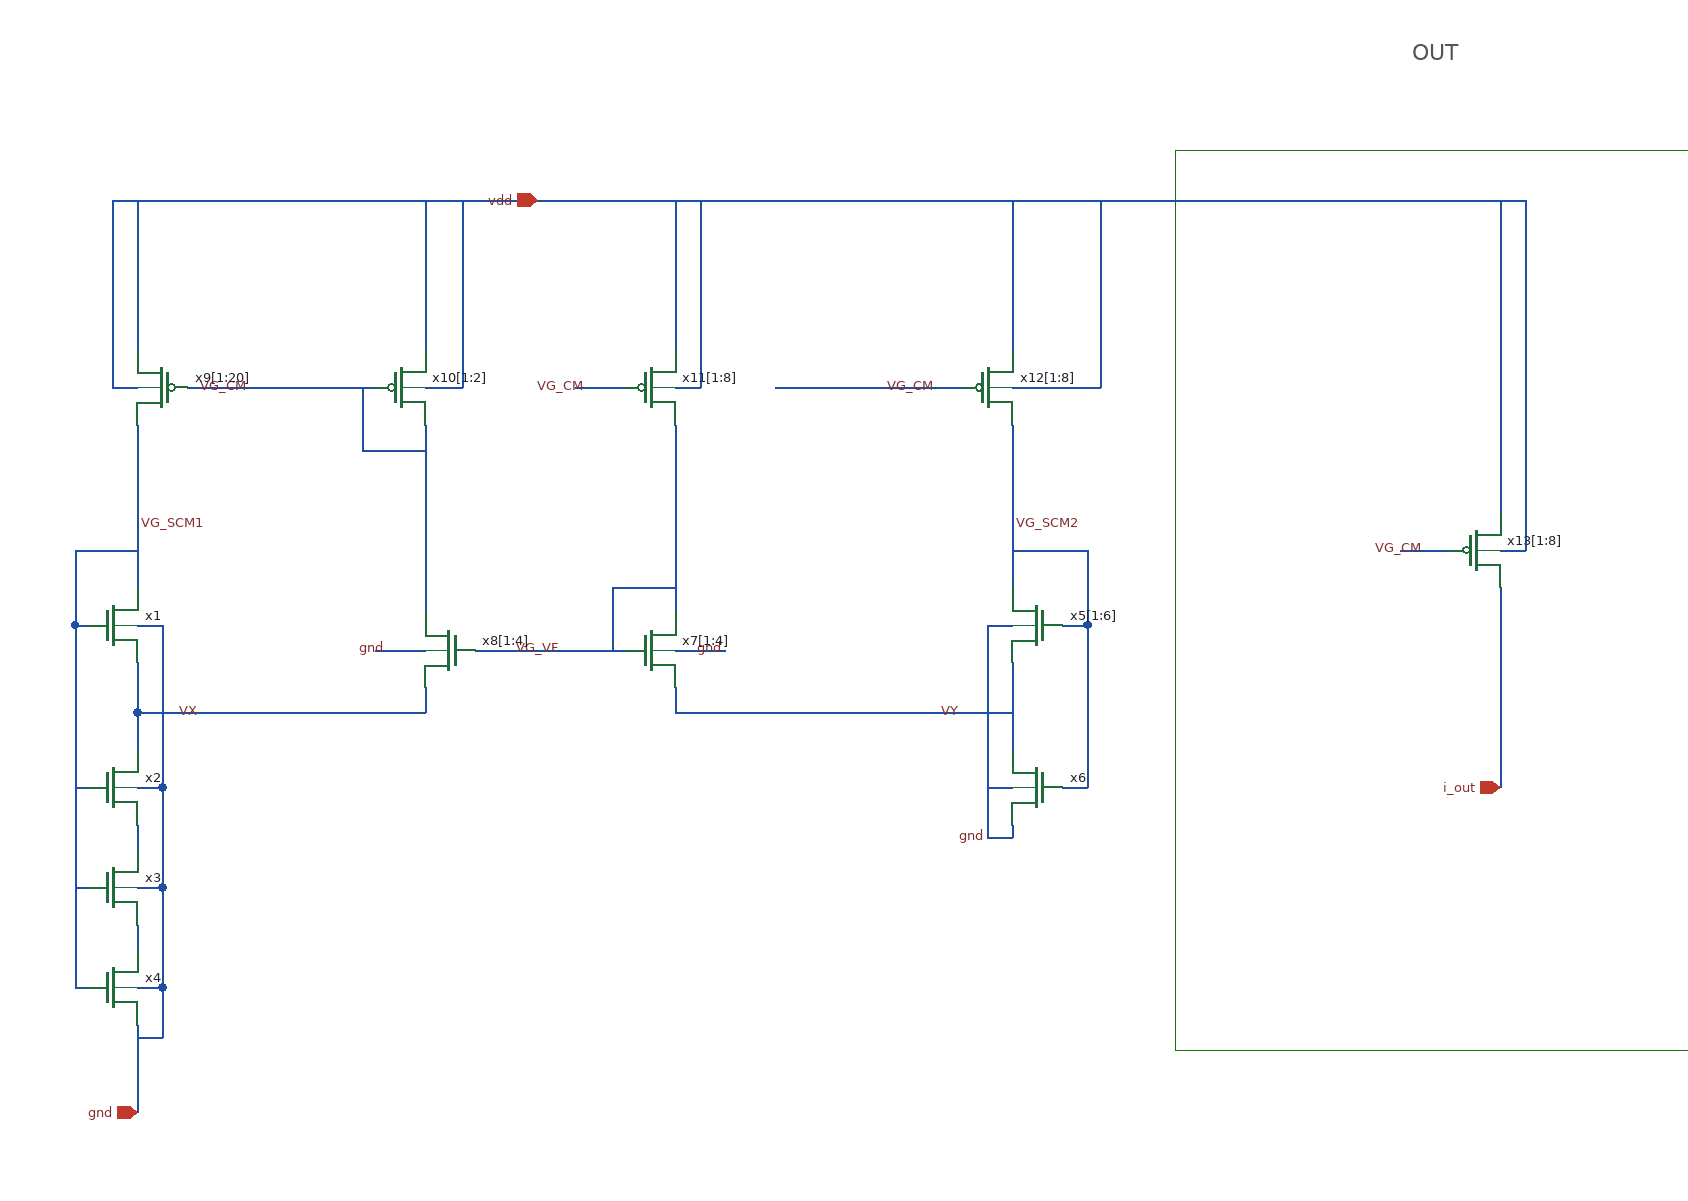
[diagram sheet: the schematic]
v {xschem version=3.4.5 file_version=1.2
}
G {}
K {}
V {}
S {}
E {}
L 4 880 -410 880 310 {}
L 4 880 310 1340 310 {}
L 4 1340 -410 1340 310 {}
L 4 880 -410 1340 -410 {}
T {OUT} 1070 -500 0 0 1 1 {}
N 50 330 50 360 {
lab=gnd}
N 50 310 50 330 {
lab=gnd}
N 1140 40 1140 60 {
lab=i_out}
N 1140 60 1140 70 {
lab=i_out}
N 1140 -370 1140 -150 {
lab=vdd}
N 1140 -30 1140 40 {
lab=i_out}
N 1140 70 1140 100 {
lab=i_out}
N 400 -220 440 -220 {
lab=VG_CM}
N 1060 -90 1100 -90 {
lab=VG_CM}
N 1140 -150 1140 -120 {
lab=vdd}
N 1140 -60 1140 -30 {
lab=i_out}
N 750 -280 750 -250 {
lab=vdd}
N 750 -220 820 -220 {
lab=vdd}
N 50 -370 50 -250 {
lab=vdd}
N 30 -220 50 -220 {
lab=vdd}
N 30 -370 30 -220 {
lab=vdd}
N 280 -370 280 -250 {
lab=vdd}
N 280 -220 310 -220 {
lab=vdd}
N 310 -370 310 -220 {
lab=vdd}
N 230 -220 230 -170 {
lab=VG_CM}
N 230 -170 280 -170 {
lab=VG_CM}
N 480 -370 480 -250 {
lab=vdd}
N 480 -220 500 -220 {
lab=vdd}
N 500 -370 500 -220 {
lab=vdd}
N 750 -370 750 -280 {
lab=vdd}
N 820 -370 820 -220 {
lab=vdd}
N -0 -30 10 -30 {
lab=VG_SCM1}
N 0 -90 0 -30 {
lab=VG_SCM1}
N 0 -90 50 -90 {
lab=VG_SCM1}
N 0 -30 -0 200 {
lab=VG_SCM1}
N 0 100 10 100 {
lab=VG_SCM1}
N 0 180 10 180 {
lab=VG_SCM1}
N 50 40 50 70 {
lab=VX}
N 50 -0 50 40 {
lab=VX}
N 50 130 50 150 {
lab=#net1}
N 70 100 70 180 {
lab=gnd}
N 70 -30 70 100 {
lab=gnd}
N 50 -30 70 -30 {
lab=gnd}
N 0 260 10 260 {
lab=VG_SCM1}
N 0 200 0 260 {
lab=VG_SCM1}
N 50 210 50 230 {
lab=#net2}
N 70 180 70 260 {
lab=gnd}
N 50 260 70 260 {
lab=gnd}
N 50 290 50 310 {
lab=gnd}
N 70 260 70 300 {
lab=gnd}
N 50 300 70 300 {
lab=gnd}
N 240 -10 280 -10 {
lab=gnd}
N 480 -10 520 -10 {
lab=gnd}
N 90 -220 240 -220 {
lab=VG_CM}
N 560 -220 710 -220 {
lab=VG_CM}
N 750 -80 750 -60 {
lab=VG_SCM2}
N 790 -30 810 -30 {
lab=VG_SCM2}
N 810 -90 810 -30 {
lab=VG_SCM2}
N 750 -90 810 -90 {
lab=VG_SCM2}
N 50 40 280 40 {
lab=VX}
N 480 40 710 40 {
lab=VY}
N 710 40 750 40 {
lab=VY}
N 750 0 750 70 {
lab=VY}
N 730 -30 750 -30 {
lab=gnd}
N 730 100 750 100 {
lab=gnd}
N 810 -30 810 100 {
lab=VG_SCM2}
N 790 100 810 100 {
lab=VG_SCM2}
N 750 130 750 140 {
lab=gnd}
N 730 140 750 140 {
lab=gnd}
N 730 -30 730 140 {
lab=gnd}
N 1140 -90 1160 -90 {
lab=vdd}
N 1160 -370 1160 -90 {
lab=vdd}
N 30 -370 1160 -370 {
lab=vdd}
N 50 -190 50 -180 {
lab=VG_SCM1}
N 50 -120 50 -60 {
lab=VG_SCM1}
N 280 -190 280 -160 {
lab=VG_CM}
N 480 -190 480 -170 {
lab=VG_VF}
N 750 -190 750 -180 {
lab=VG_SCM2}
N 750 -120 750 -80 {
lab=VG_SCM2}
N 280 -160 280 -100 {
lab=VG_CM}
N 480 -170 480 -110 {
lab=VG_VF}
N 750 -180 750 -120 {
lab=VG_SCM2}
N 50 -180 50 -120 {
lab=VG_SCM1}
N 50 100 70 100 {
lab=gnd}
N 50 180 70 180 {
lab=gnd}
N 280 20 280 40 {
lab=VX}
N 280 -100 280 -40 {
lab=VG_CM}
N 320 -10 440 -10 {
lab=VG_VF}
N 480 -110 480 -40 {
lab=VG_VF}
N 430 -60 430 -10 {
lab=VG_VF}
N 430 -60 480 -60 {
lab=VG_VF}
N 480 20 480 40 {
lab=VY}
C {devices/lab_wire.sym} 250 -10 0 0 {name=p26 sig_type=std_logic lab=gnd}
C {devices/lab_wire.sym} 520 -10 0 0 {name=p27 sig_type=std_logic lab=gnd}
C {devices/lab_wire.sym} 350 -10 0 1 {name=p34 sig_type=std_logic lab=VG_VF
}
C {devices/lab_wire.sym} 410 -220 0 0 {name=p51 sig_type=std_logic lab=VG_CM
}
C {devices/lab_wire.sym} 710 40 0 0 {name=p52 sig_type=std_logic lab=VY}
C {devices/lab_wire.sym} 50 -110 0 1 {name=p58 sig_type=std_logic lab=VG_SCM1}
C {devices/lab_wire.sym} 80.625 40 0 1 {name=p59 sig_type=std_logic lab=VX}
C {devices/lab_wire.sym} 750 -110 0 1 {name=p67 sig_type=std_logic lab=VG_SCM2}
C {devices/iopin.sym} 370 -370 3 0 {name=p55 lab=vdd}
C {devices/iopin.sym} 50 360 1 0 {name=p56 lab=gnd}
C {devices/iopin.sym} 1140 100 1 0 {name=p68 lab=i_out}
C {devices/lab_wire.sym} 140 -220 0 0 {name=p13 sig_type=std_logic lab=VG_CM}
C {devices/lab_wire.sym} 690 -220 0 0 {name=p7 sig_type=std_logic lab=VG_CM
}
C {devices/lab_wire.sym} 1080 -90 0 0 {name=p2 sig_type=std_logic lab=VG_CM
}
C {devices/lab_wire.sym} 730 140 0 0 {name=p1 sig_type=std_logic lab=gnd}
C {symbols_vr/NMOS_matrix1_SCM1.sym} 30 -30 0 0 {name=x1}
C {symbols_vr/NMOS_matrix1_SCM1.sym} 30 100 0 0 {name=x2}
C {symbols_vr/NMOS_matrix1_SCM1.sym} 30 180 0 0 {name=x3}
C {symbols_vr/NMOS_matrix2_SCM1.sym} 30 260 0 0 {name=x4}
C {symbols_vr/NMOS_matrix1_SCM2.sym} 770 -30 0 1 {name=x5[1:6]}
C {symbols_vr/NMOS_matrix2_SCM2.sym} 770 100 0 1 {name=x6}
C {symbols_vr/NMOS_matrix_VF.sym} 460 -10 0 0 {name=x7[1:4]}
C {symbols_vr/NMOS_matrix_VF.sym} 300 -10 0 1 {name=x8[1:4]}
C {symbols_vr/PMOS_matrix_CM2.sym} 70 -220 0 1 {name=x9[1:20]}
C {symbols_vr/PMOS_matrix_CM1.sym} 260 -220 0 0 {name=x10[1:2]}
C {symbols_vr/PMOS_matrix_CM2.sym} 460 -220 0 0 {name=x11[1:8]}
C {symbols_vr/PMOS_matrix_CM2.sym} 730 -220 0 0 {name=x12[1:8]}
C {symbols_vr/PMOS_matrix_CM2.sym} 1120 -90 0 0 {name=x13[1:8]}
